# Generated deterministically by seda-macro-lef-normalizer-v1; recipe orfs-asap7-fakeram-m4-v1.
VERSION 5.8 ;
BUSBITCHARS "[]" ;
DIVIDERCHAR "/" ;

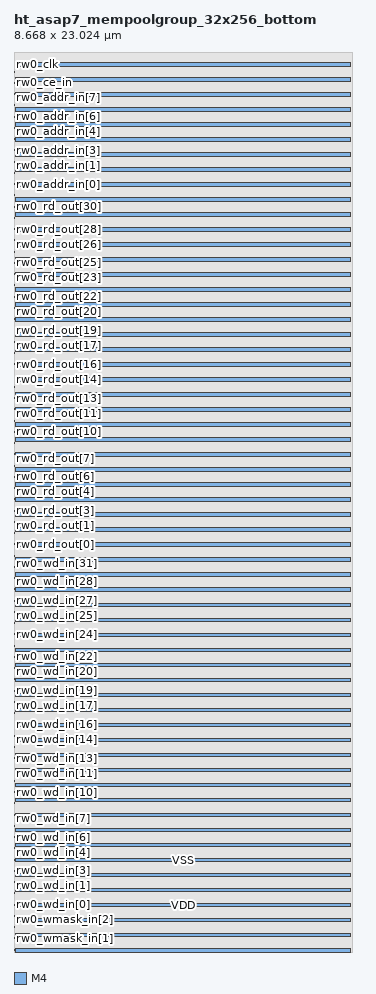
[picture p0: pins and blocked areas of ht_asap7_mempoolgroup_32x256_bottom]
MACRO ht_asap7_mempoolgroup_32x256_bottom
  FOREIGN ht_asap7_mempoolgroup_32x256_bottom 0 0 ;
  CLASS COVER ;
  ORIGIN 0 0 ;
  SIZE 8.668 BY 23.024 ;
  SYMMETRY X Y R90 ;
  PIN rw0_wmask_in[0]
    DIRECTION INPUT ;
    USE SIGNAL ;
    SHAPE ABUTMENT ;
    PORT
      LAYER M4 ;
      RECT 0 0.048 0.024 0.072 ;
    END
  END rw0_wmask_in[0]
  PIN rw0_wmask_in[1]
    DIRECTION INPUT ;
    USE SIGNAL ;
    SHAPE ABUTMENT ;
    PORT
      LAYER M4 ;
      RECT 0 0.336 0.024 0.36 ;
    END
  END rw0_wmask_in[1]
  PIN rw0_wmask_in[2]
    DIRECTION INPUT ;
    USE SIGNAL ;
    SHAPE ABUTMENT ;
    PORT
      LAYER M4 ;
      RECT 0 0.624 0.024 0.648 ;
    END
  END rw0_wmask_in[2]
  PIN rw0_wmask_in[3]
    DIRECTION INPUT ;
    USE SIGNAL ;
    SHAPE ABUTMENT ;
    PORT
      LAYER M4 ;
      RECT 0 0.912 0.024 0.936 ;
    END
  END rw0_wmask_in[3]
  PIN rw0_wd_in[0]
    DIRECTION INPUT ;
    USE SIGNAL ;
    SHAPE ABUTMENT ;
    PORT
      LAYER M4 ;
      RECT 0 1.2 0.024 1.224 ;
    END
  END rw0_wd_in[0]
  PIN rw0_wd_in[1]
    DIRECTION INPUT ;
    USE SIGNAL ;
    SHAPE ABUTMENT ;
    PORT
      LAYER M4 ;
      RECT 0 1.488 0.024 1.512 ;
    END
  END rw0_wd_in[1]
  PIN rw0_wd_in[2]
    DIRECTION INPUT ;
    USE SIGNAL ;
    SHAPE ABUTMENT ;
    PORT
      LAYER M4 ;
      RECT 0 1.776 0.024 1.8 ;
    END
  END rw0_wd_in[2]
  PIN rw0_wd_in[3]
    DIRECTION INPUT ;
    USE SIGNAL ;
    SHAPE ABUTMENT ;
    PORT
      LAYER M4 ;
      RECT 0 2.064 0.024 2.088 ;
    END
  END rw0_wd_in[3]
  PIN rw0_wd_in[4]
    DIRECTION INPUT ;
    USE SIGNAL ;
    SHAPE ABUTMENT ;
    PORT
      LAYER M4 ;
      RECT 0 2.352 0.024 2.376 ;
    END
  END rw0_wd_in[4]
  PIN rw0_wd_in[5]
    DIRECTION INPUT ;
    USE SIGNAL ;
    SHAPE ABUTMENT ;
    PORT
      LAYER M4 ;
      RECT 0 2.64 0.024 2.664 ;
    END
  END rw0_wd_in[5]
  PIN rw0_wd_in[6]
    DIRECTION INPUT ;
    USE SIGNAL ;
    SHAPE ABUTMENT ;
    PORT
      LAYER M4 ;
      RECT 0 2.928 0.024 2.952 ;
    END
  END rw0_wd_in[6]
  PIN rw0_wd_in[7]
    DIRECTION INPUT ;
    USE SIGNAL ;
    SHAPE ABUTMENT ;
    PORT
      LAYER M4 ;
      RECT 0 3.216 0.024 3.24 ;
    END
  END rw0_wd_in[7]
  PIN rw0_wd_in[8]
    DIRECTION INPUT ;
    USE SIGNAL ;
    SHAPE ABUTMENT ;
    PORT
      LAYER M4 ;
      RECT 0 3.504 0.024 3.528 ;
    END
  END rw0_wd_in[8]
  PIN rw0_wd_in[9]
    DIRECTION INPUT ;
    USE SIGNAL ;
    SHAPE ABUTMENT ;
    PORT
      LAYER M4 ;
      RECT 0 3.792 0.024 3.816 ;
    END
  END rw0_wd_in[9]
  PIN rw0_wd_in[10]
    DIRECTION INPUT ;
    USE SIGNAL ;
    SHAPE ABUTMENT ;
    PORT
      LAYER M4 ;
      RECT 0 4.08 0.024 4.104 ;
    END
  END rw0_wd_in[10]
  PIN rw0_wd_in[11]
    DIRECTION INPUT ;
    USE SIGNAL ;
    SHAPE ABUTMENT ;
    PORT
      LAYER M4 ;
      RECT 0 4.368 0.024 4.392 ;
    END
  END rw0_wd_in[11]
  PIN rw0_wd_in[12]
    DIRECTION INPUT ;
    USE SIGNAL ;
    SHAPE ABUTMENT ;
    PORT
      LAYER M4 ;
      RECT 0 4.656 0.024 4.68 ;
    END
  END rw0_wd_in[12]
  PIN rw0_wd_in[13]
    DIRECTION INPUT ;
    USE SIGNAL ;
    SHAPE ABUTMENT ;
    PORT
      LAYER M4 ;
      RECT 0 4.944 0.024 4.968 ;
    END
  END rw0_wd_in[13]
  PIN rw0_wd_in[14]
    DIRECTION INPUT ;
    USE SIGNAL ;
    SHAPE ABUTMENT ;
    PORT
      LAYER M4 ;
      RECT 0 5.232 0.024 5.256 ;
    END
  END rw0_wd_in[14]
  PIN rw0_wd_in[15]
    DIRECTION INPUT ;
    USE SIGNAL ;
    SHAPE ABUTMENT ;
    PORT
      LAYER M4 ;
      RECT 0 5.52 0.024 5.544 ;
    END
  END rw0_wd_in[15]
  PIN rw0_wd_in[16]
    DIRECTION INPUT ;
    USE SIGNAL ;
    SHAPE ABUTMENT ;
    PORT
      LAYER M4 ;
      RECT 0 5.808 0.024 5.832 ;
    END
  END rw0_wd_in[16]
  PIN rw0_wd_in[17]
    DIRECTION INPUT ;
    USE SIGNAL ;
    SHAPE ABUTMENT ;
    PORT
      LAYER M4 ;
      RECT 0 6.096 0.024 6.12 ;
    END
  END rw0_wd_in[17]
  PIN rw0_wd_in[18]
    DIRECTION INPUT ;
    USE SIGNAL ;
    SHAPE ABUTMENT ;
    PORT
      LAYER M4 ;
      RECT 0 6.384 0.024 6.408 ;
    END
  END rw0_wd_in[18]
  PIN rw0_wd_in[19]
    DIRECTION INPUT ;
    USE SIGNAL ;
    SHAPE ABUTMENT ;
    PORT
      LAYER M4 ;
      RECT 0 6.672 0.024 6.696 ;
    END
  END rw0_wd_in[19]
  PIN rw0_wd_in[20]
    DIRECTION INPUT ;
    USE SIGNAL ;
    SHAPE ABUTMENT ;
    PORT
      LAYER M4 ;
      RECT 0 6.96 0.024 6.984 ;
    END
  END rw0_wd_in[20]
  PIN rw0_wd_in[21]
    DIRECTION INPUT ;
    USE SIGNAL ;
    SHAPE ABUTMENT ;
    PORT
      LAYER M4 ;
      RECT 0 7.248 0.024 7.272 ;
    END
  END rw0_wd_in[21]
  PIN rw0_wd_in[22]
    DIRECTION INPUT ;
    USE SIGNAL ;
    SHAPE ABUTMENT ;
    PORT
      LAYER M4 ;
      RECT 0 7.536 0.024 7.56 ;
    END
  END rw0_wd_in[22]
  PIN rw0_wd_in[23]
    DIRECTION INPUT ;
    USE SIGNAL ;
    SHAPE ABUTMENT ;
    PORT
      LAYER M4 ;
      RECT 0 7.824 0.024 7.848 ;
    END
  END rw0_wd_in[23]
  PIN rw0_wd_in[24]
    DIRECTION INPUT ;
    USE SIGNAL ;
    SHAPE ABUTMENT ;
    PORT
      LAYER M4 ;
      RECT 0 8.112 0.024 8.136 ;
    END
  END rw0_wd_in[24]
  PIN rw0_wd_in[25]
    DIRECTION INPUT ;
    USE SIGNAL ;
    SHAPE ABUTMENT ;
    PORT
      LAYER M4 ;
      RECT 0 8.4 0.024 8.424 ;
    END
  END rw0_wd_in[25]
  PIN rw0_wd_in[26]
    DIRECTION INPUT ;
    USE SIGNAL ;
    SHAPE ABUTMENT ;
    PORT
      LAYER M4 ;
      RECT 0 8.688 0.024 8.712 ;
    END
  END rw0_wd_in[26]
  PIN rw0_wd_in[27]
    DIRECTION INPUT ;
    USE SIGNAL ;
    SHAPE ABUTMENT ;
    PORT
      LAYER M4 ;
      RECT 0 8.976 0.024 9 ;
    END
  END rw0_wd_in[27]
  PIN rw0_wd_in[28]
    DIRECTION INPUT ;
    USE SIGNAL ;
    SHAPE ABUTMENT ;
    PORT
      LAYER M4 ;
      RECT 0 9.264 0.024 9.288 ;
    END
  END rw0_wd_in[28]
  PIN rw0_wd_in[29]
    DIRECTION INPUT ;
    USE SIGNAL ;
    SHAPE ABUTMENT ;
    PORT
      LAYER M4 ;
      RECT 0 9.552 0.024 9.576 ;
    END
  END rw0_wd_in[29]
  PIN rw0_wd_in[30]
    DIRECTION INPUT ;
    USE SIGNAL ;
    SHAPE ABUTMENT ;
    PORT
      LAYER M4 ;
      RECT 0 9.84 0.024 9.864 ;
    END
  END rw0_wd_in[30]
  PIN rw0_wd_in[31]
    DIRECTION INPUT ;
    USE SIGNAL ;
    SHAPE ABUTMENT ;
    PORT
      LAYER M4 ;
      RECT 0 10.128 0.024 10.152 ;
    END
  END rw0_wd_in[31]
  PIN rw0_rd_out[0]
    DIRECTION OUTPUT ;
    USE SIGNAL ;
    SHAPE ABUTMENT ;
    PORT
      LAYER M4 ;
      RECT 0 10.416 0.024 10.44 ;
    END
  END rw0_rd_out[0]
  PIN rw0_rd_out[1]
    DIRECTION OUTPUT ;
    USE SIGNAL ;
    SHAPE ABUTMENT ;
    PORT
      LAYER M4 ;
      RECT 0 10.704 0.024 10.728 ;
    END
  END rw0_rd_out[1]
  PIN rw0_rd_out[2]
    DIRECTION OUTPUT ;
    USE SIGNAL ;
    SHAPE ABUTMENT ;
    PORT
      LAYER M4 ;
      RECT 0 10.992 0.024 11.016 ;
    END
  END rw0_rd_out[2]
  PIN rw0_rd_out[3]
    DIRECTION OUTPUT ;
    USE SIGNAL ;
    SHAPE ABUTMENT ;
    PORT
      LAYER M4 ;
      RECT 0 11.28 0.024 11.304 ;
    END
  END rw0_rd_out[3]
  PIN rw0_rd_out[4]
    DIRECTION OUTPUT ;
    USE SIGNAL ;
    SHAPE ABUTMENT ;
    PORT
      LAYER M4 ;
      RECT 0 11.568 0.024 11.592 ;
    END
  END rw0_rd_out[4]
  PIN rw0_rd_out[5]
    DIRECTION OUTPUT ;
    USE SIGNAL ;
    SHAPE ABUTMENT ;
    PORT
      LAYER M4 ;
      RECT 0 11.856 0.024 11.88 ;
    END
  END rw0_rd_out[5]
  PIN rw0_rd_out[6]
    DIRECTION OUTPUT ;
    USE SIGNAL ;
    SHAPE ABUTMENT ;
    PORT
      LAYER M4 ;
      RECT 0 12.144 0.024 12.168 ;
    END
  END rw0_rd_out[6]
  PIN rw0_rd_out[7]
    DIRECTION OUTPUT ;
    USE SIGNAL ;
    SHAPE ABUTMENT ;
    PORT
      LAYER M4 ;
      RECT 0 12.432 0.024 12.456 ;
    END
  END rw0_rd_out[7]
  PIN rw0_rd_out[8]
    DIRECTION OUTPUT ;
    USE SIGNAL ;
    SHAPE ABUTMENT ;
    PORT
      LAYER M4 ;
      RECT 0 12.72 0.024 12.744 ;
    END
  END rw0_rd_out[8]
  PIN rw0_rd_out[9]
    DIRECTION OUTPUT ;
    USE SIGNAL ;
    SHAPE ABUTMENT ;
    PORT
      LAYER M4 ;
      RECT 0 13.008 0.024 13.032 ;
    END
  END rw0_rd_out[9]
  PIN rw0_rd_out[10]
    DIRECTION OUTPUT ;
    USE SIGNAL ;
    SHAPE ABUTMENT ;
    PORT
      LAYER M4 ;
      RECT 0 13.296 0.024 13.32 ;
    END
  END rw0_rd_out[10]
  PIN rw0_rd_out[11]
    DIRECTION OUTPUT ;
    USE SIGNAL ;
    SHAPE ABUTMENT ;
    PORT
      LAYER M4 ;
      RECT 0 13.584 0.024 13.608 ;
    END
  END rw0_rd_out[11]
  PIN rw0_rd_out[12]
    DIRECTION OUTPUT ;
    USE SIGNAL ;
    SHAPE ABUTMENT ;
    PORT
      LAYER M4 ;
      RECT 0 13.872 0.024 13.896 ;
    END
  END rw0_rd_out[12]
  PIN rw0_rd_out[13]
    DIRECTION OUTPUT ;
    USE SIGNAL ;
    SHAPE ABUTMENT ;
    PORT
      LAYER M4 ;
      RECT 0 14.16 0.024 14.184 ;
    END
  END rw0_rd_out[13]
  PIN rw0_rd_out[14]
    DIRECTION OUTPUT ;
    USE SIGNAL ;
    SHAPE ABUTMENT ;
    PORT
      LAYER M4 ;
      RECT 0 14.448 0.024 14.472 ;
    END
  END rw0_rd_out[14]
  PIN rw0_rd_out[15]
    DIRECTION OUTPUT ;
    USE SIGNAL ;
    SHAPE ABUTMENT ;
    PORT
      LAYER M4 ;
      RECT 0 14.736 0.024 14.76 ;
    END
  END rw0_rd_out[15]
  PIN rw0_rd_out[16]
    DIRECTION OUTPUT ;
    USE SIGNAL ;
    SHAPE ABUTMENT ;
    PORT
      LAYER M4 ;
      RECT 0 15.024 0.024 15.048 ;
    END
  END rw0_rd_out[16]
  PIN rw0_rd_out[17]
    DIRECTION OUTPUT ;
    USE SIGNAL ;
    SHAPE ABUTMENT ;
    PORT
      LAYER M4 ;
      RECT 0 15.312 0.024 15.336 ;
    END
  END rw0_rd_out[17]
  PIN rw0_rd_out[18]
    DIRECTION OUTPUT ;
    USE SIGNAL ;
    SHAPE ABUTMENT ;
    PORT
      LAYER M4 ;
      RECT 0 15.6 0.024 15.624 ;
    END
  END rw0_rd_out[18]
  PIN rw0_rd_out[19]
    DIRECTION OUTPUT ;
    USE SIGNAL ;
    SHAPE ABUTMENT ;
    PORT
      LAYER M4 ;
      RECT 0 15.888 0.024 15.912 ;
    END
  END rw0_rd_out[19]
  PIN rw0_rd_out[20]
    DIRECTION OUTPUT ;
    USE SIGNAL ;
    SHAPE ABUTMENT ;
    PORT
      LAYER M4 ;
      RECT 0 16.176 0.024 16.2 ;
    END
  END rw0_rd_out[20]
  PIN rw0_rd_out[21]
    DIRECTION OUTPUT ;
    USE SIGNAL ;
    SHAPE ABUTMENT ;
    PORT
      LAYER M4 ;
      RECT 0 16.464 0.024 16.488 ;
    END
  END rw0_rd_out[21]
  PIN rw0_rd_out[22]
    DIRECTION OUTPUT ;
    USE SIGNAL ;
    SHAPE ABUTMENT ;
    PORT
      LAYER M4 ;
      RECT 0 16.752 0.024 16.776 ;
    END
  END rw0_rd_out[22]
  PIN rw0_rd_out[23]
    DIRECTION OUTPUT ;
    USE SIGNAL ;
    SHAPE ABUTMENT ;
    PORT
      LAYER M4 ;
      RECT 0 17.04 0.024 17.064 ;
    END
  END rw0_rd_out[23]
  PIN rw0_rd_out[24]
    DIRECTION OUTPUT ;
    USE SIGNAL ;
    SHAPE ABUTMENT ;
    PORT
      LAYER M4 ;
      RECT 0 17.328 0.024 17.352 ;
    END
  END rw0_rd_out[24]
  PIN rw0_rd_out[25]
    DIRECTION OUTPUT ;
    USE SIGNAL ;
    SHAPE ABUTMENT ;
    PORT
      LAYER M4 ;
      RECT 0 17.616 0.024 17.64 ;
    END
  END rw0_rd_out[25]
  PIN rw0_rd_out[26]
    DIRECTION OUTPUT ;
    USE SIGNAL ;
    SHAPE ABUTMENT ;
    PORT
      LAYER M4 ;
      RECT 0 17.904 0.024 17.928 ;
    END
  END rw0_rd_out[26]
  PIN rw0_rd_out[27]
    DIRECTION OUTPUT ;
    USE SIGNAL ;
    SHAPE ABUTMENT ;
    PORT
      LAYER M4 ;
      RECT 0 18.192 0.024 18.216 ;
    END
  END rw0_rd_out[27]
  PIN rw0_rd_out[28]
    DIRECTION OUTPUT ;
    USE SIGNAL ;
    SHAPE ABUTMENT ;
    PORT
      LAYER M4 ;
      RECT 0 18.48 0.024 18.504 ;
    END
  END rw0_rd_out[28]
  PIN rw0_rd_out[29]
    DIRECTION OUTPUT ;
    USE SIGNAL ;
    SHAPE ABUTMENT ;
    PORT
      LAYER M4 ;
      RECT 0 18.768 0.024 18.792 ;
    END
  END rw0_rd_out[29]
  PIN rw0_rd_out[30]
    DIRECTION OUTPUT ;
    USE SIGNAL ;
    SHAPE ABUTMENT ;
    PORT
      LAYER M4 ;
      RECT 0 19.056 0.024 19.08 ;
    END
  END rw0_rd_out[30]
  PIN rw0_rd_out[31]
    DIRECTION OUTPUT ;
    USE SIGNAL ;
    SHAPE ABUTMENT ;
    PORT
      LAYER M4 ;
      RECT 0 19.344 0.024 19.368 ;
    END
  END rw0_rd_out[31]
  PIN rw0_addr_in[0]
    DIRECTION INPUT ;
    USE SIGNAL ;
    SHAPE ABUTMENT ;
    PORT
      LAYER M4 ;
      RECT 0 19.632 0.024 19.656 ;
    END
  END rw0_addr_in[0]
  PIN rw0_addr_in[1]
    DIRECTION INPUT ;
    USE SIGNAL ;
    SHAPE ABUTMENT ;
    PORT
      LAYER M4 ;
      RECT 0 19.92 0.024 19.944 ;
    END
  END rw0_addr_in[1]
  PIN rw0_addr_in[2]
    DIRECTION INPUT ;
    USE SIGNAL ;
    SHAPE ABUTMENT ;
    PORT
      LAYER M4 ;
      RECT 0 20.208 0.024 20.232 ;
    END
  END rw0_addr_in[2]
  PIN rw0_addr_in[3]
    DIRECTION INPUT ;
    USE SIGNAL ;
    SHAPE ABUTMENT ;
    PORT
      LAYER M4 ;
      RECT 0 20.496 0.024 20.52 ;
    END
  END rw0_addr_in[3]
  PIN rw0_addr_in[4]
    DIRECTION INPUT ;
    USE SIGNAL ;
    SHAPE ABUTMENT ;
    PORT
      LAYER M4 ;
      RECT 0 20.784 0.024 20.808 ;
    END
  END rw0_addr_in[4]
  PIN rw0_addr_in[5]
    DIRECTION INPUT ;
    USE SIGNAL ;
    SHAPE ABUTMENT ;
    PORT
      LAYER M4 ;
      RECT 0 21.072 0.024 21.096 ;
    END
  END rw0_addr_in[5]
  PIN rw0_addr_in[6]
    DIRECTION INPUT ;
    USE SIGNAL ;
    SHAPE ABUTMENT ;
    PORT
      LAYER M4 ;
      RECT 0 21.36 0.024 21.384 ;
    END
  END rw0_addr_in[6]
  PIN rw0_addr_in[7]
    DIRECTION INPUT ;
    USE SIGNAL ;
    SHAPE ABUTMENT ;
    PORT
      LAYER M4 ;
      RECT 0 21.648 0.024 21.672 ;
    END
  END rw0_addr_in[7]
  PIN rw0_we_in
    DIRECTION INPUT ;
    USE SIGNAL ;
    SHAPE ABUTMENT ;
    PORT
      LAYER M4 ;
      RECT 0 21.936 0.024 21.96 ;
    END
  END rw0_we_in
  PIN rw0_ce_in
    DIRECTION INPUT ;
    USE SIGNAL ;
    SHAPE ABUTMENT ;
    PORT
      LAYER M4 ;
      RECT 0 22.224 0.024 22.248 ;
    END
  END rw0_ce_in
  PIN rw0_clk
    DIRECTION INPUT ;
    USE SIGNAL ;
    SHAPE ABUTMENT ;
    PORT
      LAYER M4 ;
      RECT 0 22.512 0.024 22.536 ;
    END
  END rw0_clk
  PIN VSS
    DIRECTION INOUT ;
    USE GROUND ;
    PORT
      LAYER M4 ;
      RECT 0.048 0 8.62 0.096 ;
      RECT 0.048 0.768 8.62 0.864 ;
      RECT 0.048 1.536 8.62 1.632 ;
      RECT 0.048 2.304 8.62 2.4 ;
      RECT 0.048 3.072 8.62 3.168 ;
      RECT 0.048 3.84 8.62 3.936 ;
      RECT 0.048 4.608 8.62 4.704 ;
      RECT 0.048 5.376 8.62 5.472 ;
      RECT 0.048 6.144 8.62 6.24 ;
      RECT 0.048 6.912 8.62 7.008 ;
      RECT 0.048 7.68 8.62 7.776 ;
      RECT 0.048 8.448 8.62 8.544 ;
      RECT 0.048 9.216 8.62 9.312 ;
      RECT 0.048 9.984 8.62 10.08 ;
      RECT 0.048 10.752 8.62 10.848 ;
      RECT 0.048 11.52 8.62 11.616 ;
      RECT 0.048 12.288 8.62 12.384 ;
      RECT 0.048 13.056 8.62 13.152 ;
      RECT 0.048 13.824 8.62 13.92 ;
      RECT 0.048 14.592 8.62 14.688 ;
      RECT 0.048 15.36 8.62 15.456 ;
      RECT 0.048 16.128 8.62 16.224 ;
      RECT 0.048 16.896 8.62 16.992 ;
      RECT 0.048 17.664 8.62 17.76 ;
      RECT 0.048 18.432 8.62 18.528 ;
      RECT 0.048 19.2 8.62 19.296 ;
      RECT 0.048 19.968 8.62 20.064 ;
      RECT 0.048 20.736 8.62 20.832 ;
      RECT 0.048 21.504 8.62 21.6 ;
      RECT 0.048 22.272 8.62 22.368 ;
    END
  END VSS
  PIN VDD
    DIRECTION INOUT ;
    USE POWER ;
    PORT
      LAYER M4 ;
      RECT 0.048 0.384 8.62 0.48 ;
      RECT 0.048 1.152 8.62 1.248 ;
      RECT 0.048 1.92 8.62 2.016 ;
      RECT 0.048 2.688 8.62 2.784 ;
      RECT 0.048 3.456 8.62 3.552 ;
      RECT 0.048 4.224 8.62 4.32 ;
      RECT 0.048 4.992 8.62 5.088 ;
      RECT 0.048 5.76 8.62 5.856 ;
      RECT 0.048 6.528 8.62 6.624 ;
      RECT 0.048 7.296 8.62 7.392 ;
      RECT 0.048 8.064 8.62 8.16 ;
      RECT 0.048 8.832 8.62 8.928 ;
      RECT 0.048 9.6 8.62 9.696 ;
      RECT 0.048 10.368 8.62 10.464 ;
      RECT 0.048 11.136 8.62 11.232 ;
      RECT 0.048 11.904 8.62 12 ;
      RECT 0.048 12.672 8.62 12.768 ;
      RECT 0.048 13.44 8.62 13.536 ;
      RECT 0.048 14.208 8.62 14.304 ;
      RECT 0.048 14.976 8.62 15.072 ;
      RECT 0.048 15.744 8.62 15.84 ;
      RECT 0.048 16.512 8.62 16.608 ;
      RECT 0.048 17.28 8.62 17.376 ;
      RECT 0.048 18.048 8.62 18.144 ;
      RECT 0.048 18.816 8.62 18.912 ;
      RECT 0.048 19.584 8.62 19.68 ;
      RECT 0.048 20.352 8.62 20.448 ;
      RECT 0.048 21.12 8.62 21.216 ;
      RECT 0.048 21.888 8.62 21.984 ;
      RECT 0.048 22.656 8.62 22.752 ;
    END
  END VDD
  OBS
    LAYER M1 ;
    RECT 0 0 8.668 23.024 ;
    LAYER M2 ;
    RECT 0 0 8.668 23.024 ;
    LAYER M3 ;
    RECT 0 0 8.668 23.024 ;
  END
END ht_asap7_mempoolgroup_32x256_bottom

END LIBRARY
